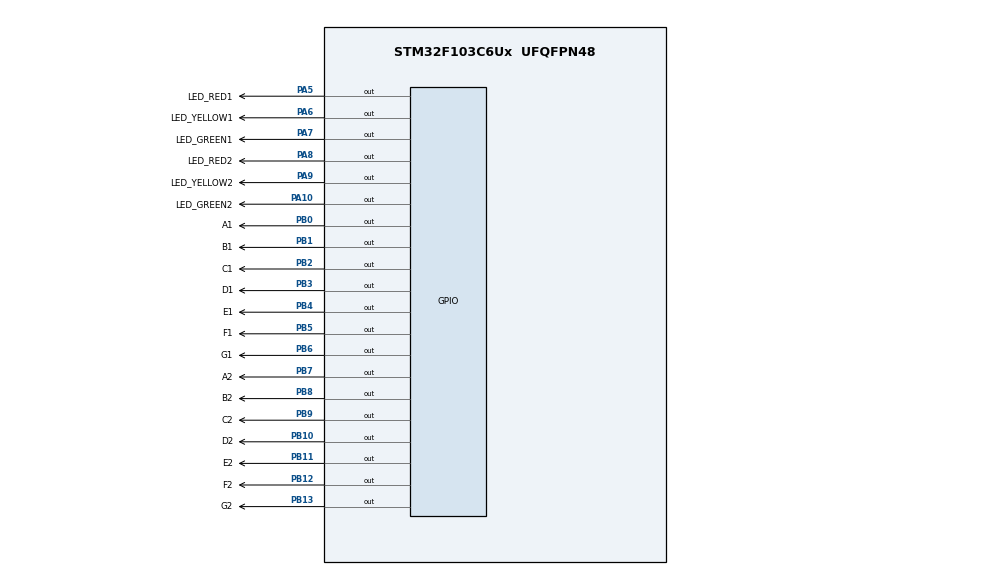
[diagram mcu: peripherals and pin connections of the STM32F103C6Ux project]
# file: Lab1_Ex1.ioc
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Mcu.Family=STM32F1
Mcu.Name=STM32F103C6Ux
Mcu.Package=UFQFPN48
NVIC.PriorityGroup=NVIC_PRIORITYGROUP_4
PA10.GPIO_Label=LED_GREEN2
PA10.Signal=GPIO_Output
PA5.GPIO_Label=LED_RED1
PA5.Signal=GPIO_Output
PA6.GPIO_Label=LED_YELLOW1
PA6.Signal=GPIO_Output
PA7.GPIO_Label=LED_GREEN1
PA7.Signal=GPIO_Output
PA8.GPIO_Label=LED_RED2
PA8.Signal=GPIO_Output
PA9.GPIO_Label=LED_YELLOW2
PA9.Signal=GPIO_Output
PB0.GPIO_Label=A1
PB0.Signal=GPIO_Output
PB1.GPIO_Label=B1
PB1.Signal=GPIO_Output
PB10.GPIO_Label=D2
PB10.Signal=GPIO_Output
PB11.GPIO_Label=E2
PB11.Signal=GPIO_Output
PB12.GPIO_Label=F2
PB12.Signal=GPIO_Output
PB13.GPIO_Label=G2
PB13.Signal=GPIO_Output
PB2.GPIO_Label=C1
PB2.Signal=GPIO_Output
PB3.GPIO_Label=D1
PB3.Signal=GPIO_Output
PB4.GPIO_Label=E1
PB4.Signal=GPIO_Output
PB5.GPIO_Label=F1
PB5.Signal=GPIO_Output
PB6.GPIO_Label=G1
PB6.Signal=GPIO_Output
PB7.GPIO_Label=A2
PB7.Signal=GPIO_Output
PB8.GPIO_Label=B2
PB8.Signal=GPIO_Output
PB9.GPIO_Label=C2
PB9.Signal=GPIO_Output
ProjectManager.HeapSize=0x200
ProjectManager.StackSize=0x400
ProjectManager.TargetToolchain=STM32CubeIDE
RCC.APB1Freq_Value=8000000
RCC.APB2Freq_Value=8000000
VP_SYS_VS_ND.Mode=No_Debug
board=custom

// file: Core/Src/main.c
/* USER CODE BEGIN Header */
/**
  ******************************************************************************
  * @file           : main.c
  * @brief          : Main program body
  ******************************************************************************
  * @attention
  *
  * <h2><center>&copy; Copyright (c) 2025 STMicroelectronics.
  * All rights reserved.</center></h2>
  *
  * This software component is licensed by ST under BSD 3-Clause license,
  * the "License"; You may not use this file except in compliance with the
  * License. You may obtain a copy of the License at:
  *                        opensource.org/licenses/BSD-3-Clause
  *
  ******************************************************************************
  */
/* USER CODE END Header */
#include "main.h"

/* USER CODE BEGIN PV */
uint16_t led[12] = {GPIO_PIN_4, GPIO_PIN_5, GPIO_PIN_6, GPIO_PIN_7,
					GPIO_PIN_8, GPIO_PIN_9, GPIO_PIN_10, GPIO_PIN_11,
					GPIO_PIN_12, GPIO_PIN_13, GPIO_PIN_14, GPIO_PIN_15};
int num = 4;
int gio = 0;
int phut = 0;
int giay = 0;
/* USER CODE END PV */

void SystemClock_Config(void);
static void MX_GPIO_Init(void);

/* USER CODE BEGIN 0 */
void test_ex6(int num);
void clearAllClock ();
void setNumberOnClock(int num);
void clearNumberOnClock(int num);
/* USER CODE END 0 */

int main(void)
{

  /* MCU Configuration--------------------------------------------------------*/

  /* Reset of all peripherals, Initializes the Flash interface and the Systick. */
  HAL_Init();

  /* Configure the system clock */
  SystemClock_Config();

  /* Initialize all configured peripherals */
  MX_GPIO_Init();

  /* Infinite loop */
  /* USER CODE BEGIN WHILE */
  clearAllClock();
  while (1)
  {
	  //Ex8_9_10
	  if (giay >= 60)
	  {
		  clearNumberOnClock((giay / 5) - 1);
		  giay = 0;
		  phut += 1;
	  }
	  else if (giay % 5 == 0 && giay != 0) clearNumberOnClock((giay / 5) - 1);
	  if (phut >= 60)
	  {
		  clearNumberOnClock((phut / 5) - 1);
		  phut = 0;
		  clearNumberOnClock(gio % 12);
		  gio += 1;
	  }
	  else if (phut % 5 == 0 && phut != 0) clearNumberOnClock((phut / 5) - 1);
	  if (gio >= 24) gio = 0;
	  setNumberOnClock(giay / 5);
	  setNumberOnClock(phut / 5);
	  setNumberOnClock(gio % 12);
	  HAL_Delay(5);
	  giay += 1;

	  // Ex6
	  /*test_ex6(num);
	  num++;
	  if (num > 11) num = 0;
	  HAL_Delay(1000);*/

	  //Ex7
	  /*HAL_Delay(5000);
	  clearAllClock();*/

    /* USER CODE END WHILE */

  }
}

void SystemClock_Config(void)
{
  RCC_OscInitTypeDef RCC_OscInitStruct = {0};
  RCC_ClkInitTypeDef RCC_ClkInitStruct = {0};

  /** Initializes the RCC Oscillators according to the specified parameters
  * in the RCC_OscInitTypeDef structure.
  */
  RCC_OscInitStruct.OscillatorType = RCC_OSCILLATORTYPE_HSI;
  RCC_OscInitStruct.HSIState = RCC_HSI_ON;
  RCC_OscInitStruct.HSICalibrationValue = RCC_HSICALIBRATION_DEFAULT;
  RCC_OscInitStruct.PLL.PLLState = RCC_PLL_NONE;
  if (HAL_RCC_OscConfig(&RCC_OscInitStruct) != HAL_OK)
  {
    Error_Handler();
  }
  /** Initializes the CPU, AHB and APB buses clocks
  */
  RCC_ClkInitStruct.ClockType = RCC_CLOCKTYPE_HCLK|RCC_CLOCKTYPE_SYSCLK
                              |RCC_CLOCKTYPE_PCLK1|RCC_CLOCKTYPE_PCLK2;
  RCC_ClkInitStruct.SYSCLKSource = RCC_SYSCLKSOURCE_HSI;
  RCC_ClkInitStruct.AHBCLKDivider = RCC_SYSCLK_DIV1;
  RCC_ClkInitStruct.APB1CLKDivider = RCC_HCLK_DIV1;
  RCC_ClkInitStruct.APB2CLKDivider = RCC_HCLK_DIV1;

  if (HAL_RCC_ClockConfig(&RCC_ClkInitStruct, FLASH_LATENCY_0) != HAL_OK)
  {
    Error_Handler();
  }
}

static void MX_GPIO_Init(void)
{
  GPIO_InitTypeDef GPIO_InitStruct = {0};

  /* GPIO Ports Clock Enable */
  __HAL_RCC_GPIOA_CLK_ENABLE();

  /*Configure GPIO pin Output Level */
  HAL_GPIO_WritePin(GPIOA, LED0_Pin|LED1_Pin|LED2_Pin|LED3_Pin
                          |LED4_Pin|LED5_Pin|LED6_Pin|LED7_Pin
                          |LED8_Pin|LED9_Pin|LED10_Pin|LED11_Pin, GPIO_PIN_RESET);

  /*Configure GPIO pins : LED0_Pin LED1_Pin LED2_Pin LED3_Pin
                           LED4_Pin LED5_Pin LED6_Pin LED7_Pin
                           LED8_Pin LED9_Pin LED10_Pin LED11_Pin */
  GPIO_InitStruct.Pin = LED0_Pin|LED1_Pin|LED2_Pin|LED3_Pin
                          |LED4_Pin|LED5_Pin|LED6_Pin|LED7_Pin
                          |LED8_Pin|LED9_Pin|LED10_Pin|LED11_Pin;
  GPIO_InitStruct.Mode = GPIO_MODE_OUTPUT_PP;
  GPIO_InitStruct.Pull = GPIO_NOPULL;
  GPIO_InitStruct.Speed = GPIO_SPEED_FREQ_LOW;
  HAL_GPIO_Init(GPIOA, &GPIO_InitStruct);

}

/* USER CODE BEGIN 4 */
void test_ex6(int num)
{
	HAL_GPIO_WritePin(GPIOA, GPIO_PIN_4|GPIO_PIN_5|GPIO_PIN_6|GPIO_PIN_7
	                         |GPIO_PIN_8|GPIO_PIN_9|GPIO_PIN_10|GPIO_PIN_11
	                         |GPIO_PIN_12|GPIO_PIN_13|GPIO_PIN_14|GPIO_PIN_15, GPIO_PIN_SET);
	if (num < 0 || num > 11) return;
	HAL_GPIO_WritePin(GPIOA, led[num], GPIO_PIN_RESET);
}
void clearAllClock ()
{
	HAL_GPIO_WritePin(GPIOA, GPIO_PIN_4|GPIO_PIN_5|GPIO_PIN_6|GPIO_PIN_7
		                     |GPIO_PIN_8|GPIO_PIN_9|GPIO_PIN_10|GPIO_PIN_11
		                     |GPIO_PIN_12|GPIO_PIN_13|GPIO_PIN_14|GPIO_PIN_15, GPIO_PIN_SET);
}
void setNumberOnClock(int num)
{
	if (num >= 12 || num < 0) return;
	HAL_GPIO_WritePin(GPIOA, led[num], GPIO_PIN_RESET);
}
void clearNumberOnClock(int num)
{
	if (num >= 12 || num < 0) return;
	HAL_GPIO_WritePin(GPIOA, led[num], GPIO_PIN_SET);
}

/* USER CODE END 4 */

void Error_Handler(void)
{
  __disable_irq();
  while (1)
  {
  }
}

/************************ (C) COPYRIGHT STMicroelectronics *****END OF FILE****/
